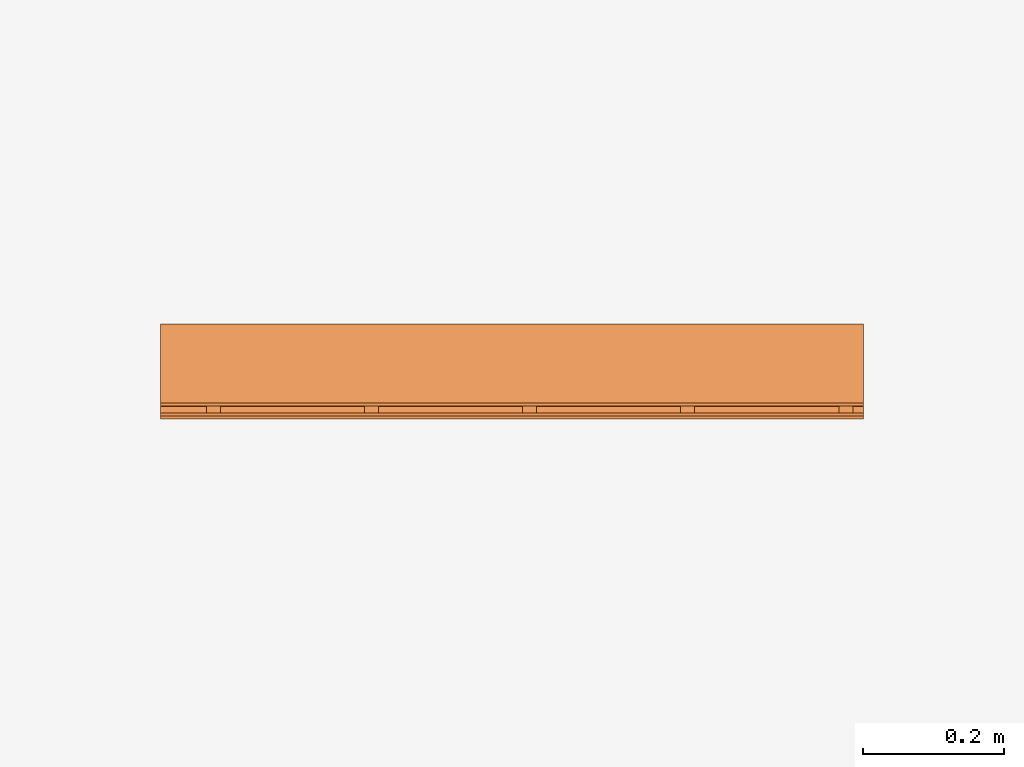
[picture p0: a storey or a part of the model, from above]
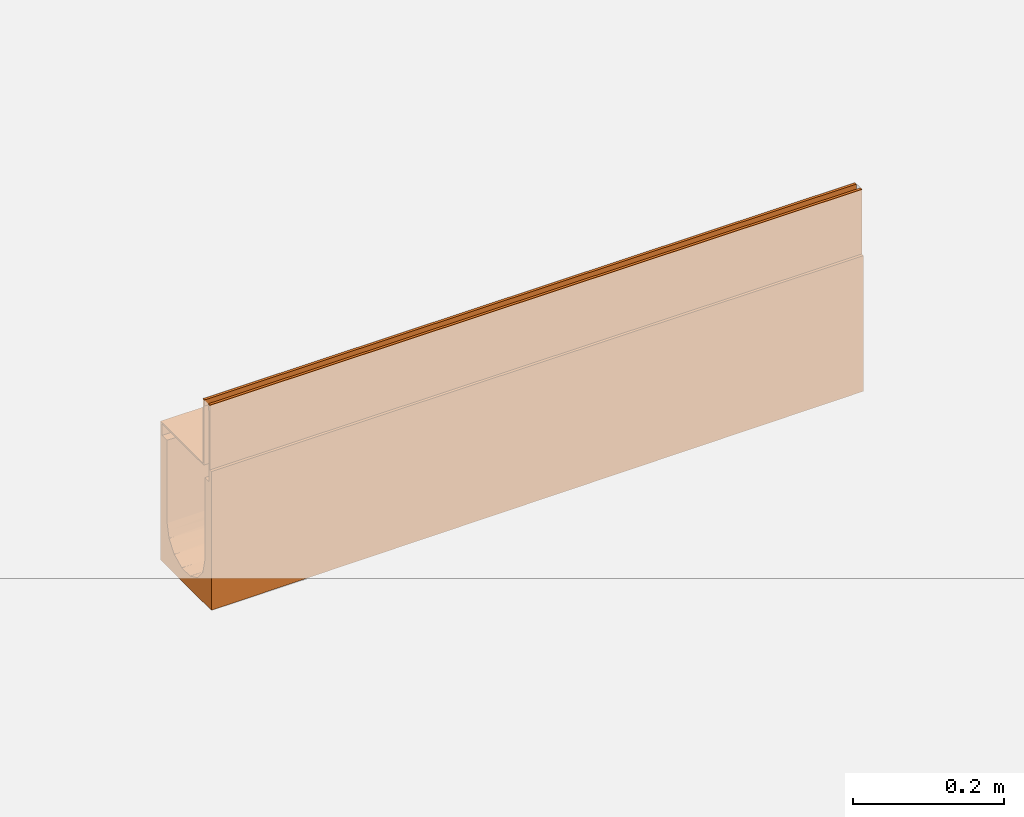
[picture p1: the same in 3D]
Properties of the parts of a building model (IFC2X3)

# File
Description: ViewDefinition [CoordinationView]
File name: 23015 - No 15 Sloping Channel - 1000mm LG - Invert Depth 200-205mm.ifc
Time: 2013-10-31T17:27:44
Written by: Autodesk Revit 2013
Made in: 20120221_2030(x64)

# IfcProject, Project Number
LongName: Project Name; Phase: Project Status

# IfcSite, Default
RefLatitude: 42, 21, 30, 344238; RefLongitude: -71, -3, -35, -194702; RefElevation: 0 mm

# IfcBuilding
Pset_BuildingCommon - NumberOfStoreys: 1
Other - Project Number: Project Number; Client Name: Owner; Project Name: Project Name; Project Status: Project Status; Project Address: ## Street City, State Zip; Project Issue Date: Issue Date

# IfcBuildingStorey, Level 1
LongName: Level 1; Elevation: 0 mm
Constraints - Elevation Base: 0; Elevation: 0 mm
Graphics - Color: 0; Line Weight: 1; Symbol at End 2 Default: yes; Line Pattern: Center; Symbol at End 1 Default: no; Symbol: M_Level Head - Circle: M_Level Head - Circle
Identity Data - Name: Level 1; Structural: no; Building Story: yes
Dimensions - Computation Height: 0 mm

# IfcBuildingElementProxy: 23015 - No 15 Sloping Channel - 1000mm LG - Invert Depth 200/205mm, Civil-Drainage-Channel-ACO-MultiDrain-M100D-Brickslot-Channel-System:23015 - No 15 Sloping Channel - 1000mm LG - Invert Depth 200/205mm:23015 - No 15 Sloping Channel - 1000mm LG - Invert Depth 200/205mm:196059
In: Level 1
Material: Steel, Galvanized, Vienite® Synthetic Resin Concrete
Construction - 23460_Load Class C250_Brickslot Grating_Galvanized Steel_1000mm Long: no; 23404_Universal Endcap (Female End): no; 23404_Universal Endcap (Male End): no; 23466_Load Class D400_Brickslot Grating_Galvanized Steel_500mm Long: no; 23467_Load Class D400_Brickslot Access Unit_Galvanised Steel_500mm Long: no; 23461_Load Class C250_Brickslot Grating_Galvanized Steel_500mm Long: no; 23462_Load Class C250_Brickslot Access Unit_Galvanised Steel_500mm Long: no; 23465_Load Class D400_Brickslot Grating_Galvanized Steel_1000mm Long: yes; Shallow Depth Channel: no; Constant Depth Junction Channel: no; Shallow Depth Channel with seal: no; 23410_Sump Unit: no; Constant Depth Channel: no; Sloping Channel: yes
Dimensions - Length: 1000 mm; Brickslot Access Unit Void Bottom Depth: -6605 mm; Brickslot Access Unit Void Depth: -6500 mm; Volume: 11126188 mm3; EndCap Position: 1000 mm; Brickslot Void Length: 1000 mm; Brickslot Void Depth: 0 mm; Custom_Void_length: 0 mm; FloorCut_Length: -1000 mm; FloorCut_Depth: 225 mm; SlopingInvertDepth: 150 mm; ShallowOverallDepth: 75 mm; ShallowInvDepth: 55 mm; Floor Cut Gap: 105 mm; GratingLength: -1000 mm; Brickslot Access Unit Floor Cut Length: 500 mm; SlopingEndInvertDepth: 155 mm; Length Drain: -1000 mm; EndCap_Height: 225 mm; FloorCut_Width: 135 mm; InvDepth: 80 mm; Depth: 150 mm; SlopingEndOverallDepth: 225 mm; Access_Custom_Void_Length: 0 mm; SlopingOverallDepth: 220 mm
Phasing - Phase Created: New Construction
Constraints - Level: Level: Level 1; Moves With Nearby Elements: no
Pset_BuildingElementProxyCommon - Reference: 23015 - No 15 Sloping Channel - 1000mm LG - Invert Depth 200/205mm
Identity Data - e-mail Technical: technical@aco.co.uk; OmniClass Number: 23.70.50.24; Watermark 2: This file is water marked and users are prohibited to reproduce, adapt, distribute this information; Cost: 0; Model: ACO MultiDrain MD Brickslot- M100D; Fax: +44 (0)1462 815895; Telephone: +44 (0)1462 816666; Assembly Code: D2040; Watermarked With: BIM Manager Premium Suite; Manufacturer: ACO Technologies plc - ACO Water Management Division; Product Code: 23015; Assembly Description: Rain Water Drainage; Maintenance guidelines: http://www.aco.co.uk/download.php?id=173; Installation guidelines: http://www.aco.co.uk/download.php?id=173; OmniClass Title: Rainwater Removal; Product Page URL: http://www.aco.co.uk/product_detail.php?id=58; Address: ACO Business Park, Hitchin Road, Shefford, Bedfordshire, United Kingdom SG17 5TE; Watermark 1: This file is the property of ACO Technologies PLC; e-mail Sales: customersupport@aco.co.uk; Type Comments: ACO MultiDrain M100D No 15 Sloping Channel 1000mm Long; Model Description: Channel drainage system; URL: www.aco.co.uk; Product brochure: http://www.aco.co.uk/download.php?id=173; Price: POA - contact ACO
Model Properties - Brickslot Grating Product code 23460: Load Class C250 - Brickslot Galvanised Steel - 1000mm long x 105mm high - 10mm Slot - Intake area - 10000mm²/m - 6.6 Kg; End Cap Product code 23404: No 306 Universal End Cap - 135mm wide x 300mm long - Spigot Ø110mm x 50mm long - Silver - Polypropylene - 0.16kg; Brickslot Grating Product code 23466: Load Class D400 - Brickslot Galvanised Steel - 500mm long x 105mm high - 10mm Slot - Intake area - 10000mm²/m - 3.3 Kg; Brickslot Access Unit Product code 23467: Load Class D400 - Brickslot Access Unit Galvanised Steel - 500mm long x 105mm high - 10mm Slot - Intake area - 10000mm²/m - 6.4 Kg; Brickslot Grating Product code 23461: Load Class C250 - Brickslot Galvanised Steel - 500mm long x 105mm high - 10mm Slot - Intake area - 10000mm²/m -3.3 Kg; Brickslot Grating Product code 23465: Load Class D400 - Brickslot Galvanised Steel - 1000mm long x 105mm high - 10mm Slot - Intake area - 10000mm²/m - 6.6 Kg; Brickslot Access Unit Product code 23462: Load Class C250 - Brickslot Access Unit Galvanised Steel - 500mm long x 105mm high - 10mm Slot - Intake area - 10000mm²/m - 6.4 Kg
General - SerialNumber: 0; TagNumber: 0
Data - Concrete Surround Volume - Load Class D 400 - Concrete Pavement: N/A; Product Weight: 17.7 Kg; Pre-formed Outlet Ø: N/A; Concrete Surround Volume - Load Class A 15 - Concrete Pavement: N/A; Product Dimensions: 1000mm x 135mm x 220mm/225mm (LxWxH); Load Class: A 15 - D 400; Hydraulic Performance: http://www.aco.co.uk/download.php?id=173; Installation - Concrete Grade: Refer to brochure; Product Standard: BS EN 1433:2002, CE marked; ACO Hydraulic Design Software: http://www.acodesign.co.uk; Channel C.S.A: N/A; Invert Depth: 200mm/205mm; Concrete Surround Volume - Load Class B 125 - C 250 - Concrete Pavement: N/A
Other - Watermarked By: www.aco.co.uk; Created By: www.aco.co.uk; Revision: 1
Materials and Finishes - Edge Rail Finish: Pre-galvanised; Channel Colour: Brown; Edge Rail Colour: Silver; Channel Material: Vienite® Synthetic Resin Concrete; Edge Rail Material: Steel
Green Building Properties - Channel Recycled Material Content: 20% minimum; Edge Rail Recyclable: Fully recyclable; Channel Recyclable: Fully recyclable; Edge Rail Recycled Material Content: Between 40% - 90%

# IfcOpeningElement: Recess (2)
In: Level 1
Dimensions - Area: 25000000 mm2; Perimeter: 20000 mm; Volume: 24967735000 mm3; Thickness: 1000 mm
Phasing - Phase Created: New Construction
Constraints - Related to Mass: no; Height Offset From Level: 0 mm; Room Bounding: yes; Level: Level: Level 1
Structural - Enable Analytical Model: no; Structural: no
Materials and Finishes - Structural Material: Earth
Construction - Function: 0; Default Thickness: 1000 mm
Analytical Properties - Heat Transfer Coefficient (U): 0.837; Absorptance: 0.1; Thermal mass: 1359800; Thermal Resistance (R): 1.19474; Roughness: 1
Graphics - Coarse Scale Fill Color: 0

# IfcSlab: Floor:Generic Floor - 1000mm, Floor:Generic Floor - 1000mm:193825
In: Level 1
PredefinedType: FLOOR; Material: Earth 1000 mm
Dimensions - Area: 25000000 mm2; Perimeter: 20000 mm; Volume: 24967735000 mm3; Thickness: 1000 mm
Phasing - Phase Created: New Construction
Constraints - Related to Mass: no; Height Offset From Level: 0 mm; Room Bounding: yes; Level: Level: Level 1
Structural - Enable Analytical Model: no; Structural: no
Pset_SlabCommon - Reference: Generic Floor - 1000mm; IsExternal: no; LoadBearing: yes
Materials and Finishes - Structural Material: Earth
Construction - Function: 0; Default Thickness: 1000 mm
Analytical Properties - Heat Transfer Coefficient (U): 0.837; Absorptance: 0.1; Thermal mass: 1359800; Thermal Resistance (R): 1.19474; Roughness: 1
Graphics - Coarse Scale Fill Color: 0
